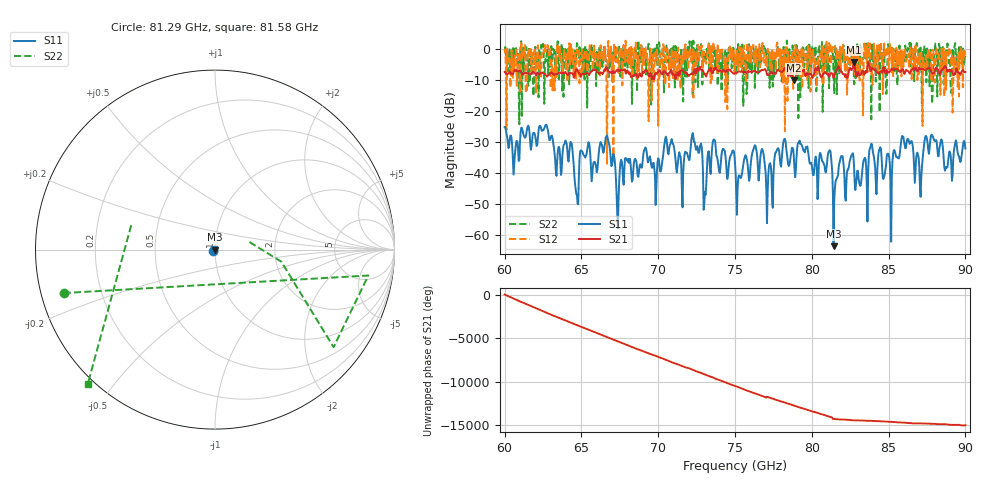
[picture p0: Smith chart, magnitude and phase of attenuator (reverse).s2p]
!Created with skrf (http://scikit-rf.org).
# GHz S RI R 50.0
!freq ReS11 ImS11 ReS21 ImS21 ReS12 ImS12 ReS22 ImS22
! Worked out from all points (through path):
!   721 points, 60 GHz to 90 GHz, reference 50 ohm
!   highest |S21| = -4.04 dB at 82.75 GHz (marker M1); lowest = -10.0 dB at 78.83 GHz (marker M2)
!   lowest |S11| = -63.8 dB at 81.42 GHz (marker M3), VSWR 1.00, Z = 50 - j0.0643 ohm
!   |S11| at or under -10 dB: start of sweep to end of sweep
!   |S22| runs from -24.3 to 2.9 dB; largest |S21 - S12| = 1.8
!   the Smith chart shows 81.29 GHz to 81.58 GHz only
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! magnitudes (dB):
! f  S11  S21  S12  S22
! 60 GHz  -25.2  -7.3  -1.0  -0.5
! 64.33 GHz  -30.2  -7.8  -4.1  0.6
! 64.71 GHz  -47.1  -6.5  0.1  2.1
! 65 GHz  -32.8  -8.5  -1.3  -3.8
! 66.71 GHz  -28.7  -6.5  -2.8  -5.4
! 67.38 GHz  -58.0  -6.9  -1.7  -3.9
! 67.96 GHz  -35.7  -6.8  -2.8  -2.2
! 70 GHz  -35.3  -7.3  -24.7  -2.6
! 70.88 GHz  -29.1  -7.0  0.0  -3.1
! 71.58 GHz  -51.2  -6.7  -2.2  -7.2
! 72.25 GHz  -27.1  -7.8  0.0  -15.3
! 73.04 GHz  -46.2  -8.2  -3.5  -1.0
! 73.62 GHz  -29.2  -6.1  0.4  -1.9
! 75 GHz  -36.7  -7.7  -3.3  -1.8
! 78.83 GHz  -35.1  -10.0  -0.2  -2.6
! 80 GHz  -37.6  -8.6  -2.3  -0.5
! 81.17 GHz  -32.7  -8.5  0.0  -3.3
! 81.42 GHz  -63.8  -9.2  0.1  -8.5
! 81.92 GHz  -34.6  -7.3  0.6  -1.4
! 82.75 GHz  -37.7  -4.0  0.2  -11.3
! 85 GHz  -34.0  -7.4  -6.5  0.2
! 90 GHz  -32.1  -7.3  -2.0  -2.5
